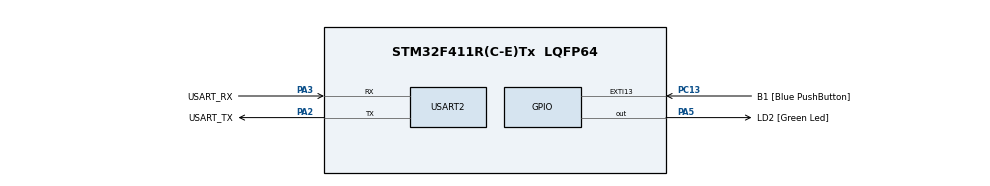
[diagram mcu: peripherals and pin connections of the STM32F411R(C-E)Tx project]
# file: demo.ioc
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Mcu.Family=STM32F4
Mcu.Name=STM32F411R(C-E)Tx
Mcu.Package=LQFP64
NVIC.PriorityGroup=NVIC_PRIORITYGROUP_0
PA13.GPIO_Label=TMS
PA13.Mode=Serial_Wire
PA13.Signal=SYS_JTMS-SWDIO
PA14.GPIO_Label=TCK
PA14.Mode=Serial_Wire
PA14.Signal=SYS_JTCK-SWCLK
PA2.GPIO_Label=USART_TX
PA2.Mode=Asynchronous
PA2.Signal=USART2_TX
PA3.GPIO_Label=USART_RX
PA3.Mode=Asynchronous
PA3.Signal=USART2_RX
PA5.GPIO_Label=LD2 [Green Led]
PA5.Signal=GPIO_Output
PB3.GPIO_Label=SWO
PB3.Signal=SYS_JTDO-SWO
PC13-ANTI_TAMP.GPIO_Label=B1 [Blue PushButton]
PC13-ANTI_TAMP.GPIO_ModeDefaultEXTI=GPIO_MODE_IT_FALLING
PC13-ANTI_TAMP.Signal=GPXTI13
PC14-OSC32_IN.Mode=LSE-External-Oscillator
PC14-OSC32_IN.Signal=RCC_OSC32_IN
PC15-OSC32_OUT.Mode=LSE-External-Oscillator
PC15-OSC32_OUT.Signal=RCC_OSC32_OUT
PH0\ -\ OSC_IN.Mode=HSE-External-Oscillator
PH0\ -\ OSC_IN.Signal=RCC_OSC_IN
PH1\ -\ OSC_OUT.Mode=HSE-External-Oscillator
PH1\ -\ OSC_OUT.Signal=RCC_OSC_OUT
ProjectManager.HeapSize=0x200
ProjectManager.StackSize=0x400
ProjectManager.TargetToolchain=Makefile
RCC.48MHZClocksFreq_Value=42000000
RCC.AHBFreq_Value=42000000
RCC.APB1CLKDivider=RCC_HCLK_DIV2
RCC.APB1Freq_Value=21000000
RCC.APB1TimFreq_Value=42000000
RCC.APB2Freq_Value=42000000
RCC.APB2TimFreq_Value=42000000
RCC.CortexFreq_Value=42000000
RCC.FLatency-AdvancedSettings=FLASH_LATENCY_1
RCC.HCLKFreq_Value=42000000
RCC.HSE_VALUE=8000000
RCC.HSI_VALUE=16000000
RCC.PLLN=336
RCC.PLLP=RCC_PLLP_DIV4
RCC.PLLSourceVirtual=RCC_PLLSOURCE_HSE
RCC.SYSCLKFreq_VALUE=42000000
RCC.SYSCLKSource=RCC_SYSCLKSOURCE_PLLCLK
RCC.VCOOutputFreq_Value=168000000
USART2.VirtualMode=VM_ASYNC
board=NUCLEO-F411RE

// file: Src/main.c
/* USER CODE BEGIN Header */
/**
  ******************************************************************************
  * @file           : main.c
  * @brief          : Main program body
  ******************************************************************************
  * @attention
  *
  * <h2><center>&copy; Copyright (c) 2020 STMicroelectronics.
  * All rights reserved.</center></h2>
  *
  * This software component is licensed by ST under BSD 3-Clause license,
  * the "License"; You may not use this file except in compliance with the
  * License. You may obtain a copy of the License at:
  *                        opensource.org/licenses/BSD-3-Clause
  *
  ******************************************************************************
  */
/* USER CODE END Header */

#include "main.h"
#include "usart.h"
#include "gpio.h"

/* USER CODE BEGIN Includes */
#include "los_base.h"
#include "los_sys.h"
#include "los_typedef.h"
#include "cmsis_os.h"
#include "los_task.ph"
// #include "los_inspect_entry.h"
/* USER CODE END Includes */

void SystemClock_Config(void);

/* USER CODE BEGIN 0 */
void task1(void)
{
  int count = 1;
  while (1)
  {
    printf("This is task1,count is %d\r\n", count++);
    LOS_TaskDelay(1000);
  }
}

/* task pid */
static UINT32 g_TskHandle;

UINT32 creat_task1()
{
  UINT32 uwRet = LOS_OK;
  TSK_INIT_PARAM_S task_init_param;

  task_init_param.usTaskPrio = 0;
  task_init_param.pcName = "task1";
  task_init_param.pfnTaskEntry = (TSK_ENTRY_FUNC)task1;
  task_init_param.uwStackSize = 0x200;

  uwRet = LOS_TaskCreate(&g_TskHandle, &task_init_param);
  if (LOS_OK != uwRet)
  {
    return uwRet;
  }
  return uwRet;
}

void task2(void)
{
  int count = 1;
  while (1)
  {
    printf("This is task2,count is %d\r\n", count++);
    LOS_TaskDelay(2000);
  }
}
UINT32 creat_task2()
{
  UINT32 uwRet = LOS_OK;
  TSK_INIT_PARAM_S task_init_param;

  task_init_param.usTaskPrio = 1;
  task_init_param.pcName = "task2";
  task_init_param.pfnTaskEntry = (TSK_ENTRY_FUNC)task2;
  task_init_param.uwStackSize = 0x200;

  uwRet = LOS_TaskCreate(&g_TskHandle, &task_init_param);
  if (LOS_OK != uwRet)
  {
    return uwRet;
  }
  return uwRet;
}
/* USER CODE END 0 */

int main(void)
{

  /* MCU Configuration--------------------------------------------------------*/

  /* Reset of all peripherals, Initializes the Flash interface and the Systick. */
  HAL_Init();

  /* Configure the system clock */
  SystemClock_Config();

  /* Initialize all configured peripherals */
  MX_GPIO_Init();
  MX_USART2_UART_Init();
  /* USER CODE BEGIN 2 */
   UINT32 uwRet = LOS_OK;
  uwRet = LOS_KernelInit();
  if (uwRet != LOS_OK)
  {
    return LOS_NOK;
  }
  uwRet = creat_task1();
  if (uwRet != LOS_OK)
  {
    return LOS_NOK;
  }
  uwRet = creat_task2();
  if (uwRet != LOS_OK)
  {
    return LOS_NOK;
  }
  LOS_Start();
  /* USER CODE END 2 */

  /* Infinite loop */
  while (1)
  {

  }
}

void SystemClock_Config(void)
{
  RCC_OscInitTypeDef RCC_OscInitStruct = {0};
  RCC_ClkInitTypeDef RCC_ClkInitStruct = {0};

  /** Configure the main internal regulator output voltage
  */
  __HAL_RCC_PWR_CLK_ENABLE();
  __HAL_PWR_VOLTAGESCALING_CONFIG(PWR_REGULATOR_VOLTAGE_SCALE1);
  /** Initializes the CPU, AHB and APB busses clocks
  */
  RCC_OscInitStruct.OscillatorType = RCC_OSCILLATORTYPE_HSI;
  RCC_OscInitStruct.HSIState = RCC_HSI_ON;
  RCC_OscInitStruct.HSICalibrationValue = RCC_HSICALIBRATION_DEFAULT;
  RCC_OscInitStruct.PLL.PLLState = RCC_PLL_ON;
  RCC_OscInitStruct.PLL.PLLSource = RCC_PLLSOURCE_HSI;
  RCC_OscInitStruct.PLL.PLLM = 16;
  RCC_OscInitStruct.PLL.PLLN = 336;
  RCC_OscInitStruct.PLL.PLLP = RCC_PLLP_DIV4;
  RCC_OscInitStruct.PLL.PLLQ = 4;
  if (HAL_RCC_OscConfig(&RCC_OscInitStruct) != HAL_OK)
  {
    Error_Handler();
  }
  /** Initializes the CPU, AHB and APB busses clocks
  */
  RCC_ClkInitStruct.ClockType = RCC_CLOCKTYPE_HCLK | RCC_CLOCKTYPE_SYSCLK | RCC_CLOCKTYPE_PCLK1 | RCC_CLOCKTYPE_PCLK2;
  RCC_ClkInitStruct.SYSCLKSource = RCC_SYSCLKSOURCE_PLLCLK;
  RCC_ClkInitStruct.AHBCLKDivider = RCC_SYSCLK_DIV1;
  RCC_ClkInitStruct.APB1CLKDivider = RCC_HCLK_DIV2;
  RCC_ClkInitStruct.APB2CLKDivider = RCC_HCLK_DIV1;

  if (HAL_RCC_ClockConfig(&RCC_ClkInitStruct, FLASH_LATENCY_2) != HAL_OK)
  {
    Error_Handler();
  }
}

void Error_Handler(void)
{
}

/************************ (C) COPYRIGHT STMicroelectronics *****END OF FILE****/
